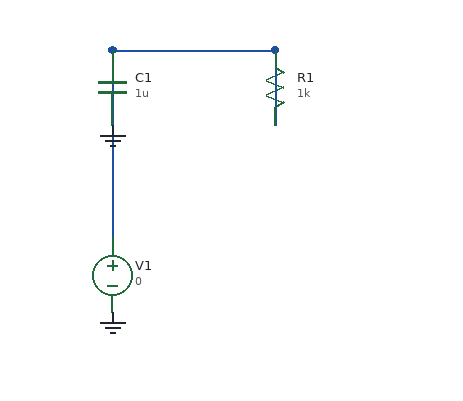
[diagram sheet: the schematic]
v {xschem version=3.4.5 file_version=1.2}
G {}
K {}
V {}
S {}
E {}
C {devices/vsource.sym} 440 -250 0 0 {name=V1
value=0}
C {devices/res.sym} 570 -400 0 0 {name=R1
value=1k}
C {devices/capa.sym} 440 -400 0 0 {name=C1
value=1u}
N 440 -280 440 -430 {lab=1}
N 440 -430 570 -430 {lab=1}
N 570 -370 570 -430 {lab=2}
N 570 -430 440 -430 {lab=2}
C {devices/gnd.sym} 440 -220 0 0 {name=l_0 lab=GND}
C {devices/gnd.sym} 440 -370 0 0 {name=l_0 lab=GND}
